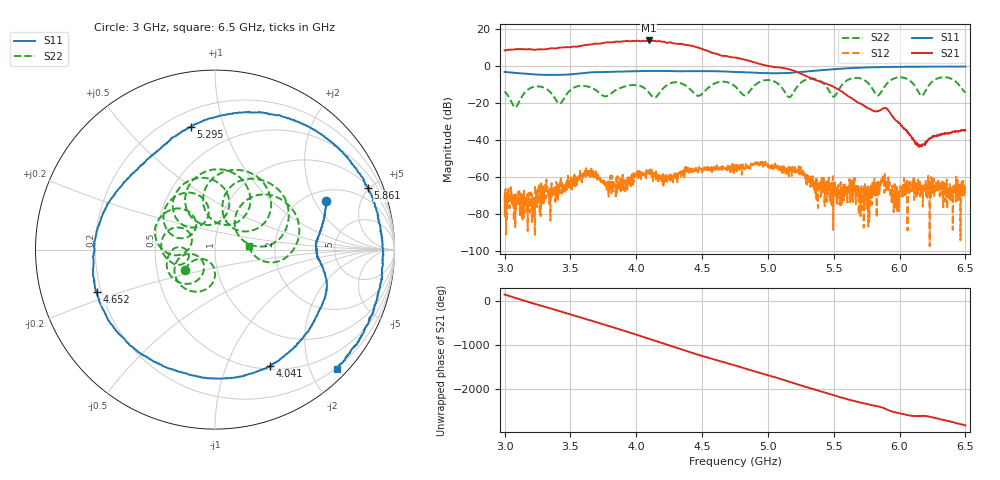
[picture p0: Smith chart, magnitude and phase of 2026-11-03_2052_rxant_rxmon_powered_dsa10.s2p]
! HEWLETT PACKARD,8720ES,MY41003347,7.72, via bringup/vna_tests.py
! rxant_rxmon_powered_dsa10
! measured 2026-11-03 20:53:22, 1601 points, 3000000000-6500000000 Hz, IF bandwidth 1000 Hz, source -40.00 dBm, kit CALK35MD
! board A, DSA 10.00 dB (set before each sweep)
# HZ S RI R 50
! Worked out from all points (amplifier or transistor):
!   1601 points, 3 GHz to 6.5 GHz, reference 50 ohm
!   highest |S21| = 13.7 dB at 4.096 GHz (marker M1)
!   |S21| within 3 dB of that: 3.577 GHz to 4.427 GHz (850.6 MHz wide, 21.3 % of centre)
!   unconditionally stable (mu >= 1): start of sweep to end of sweep
!   at 3.582 GHz: K = 97.68, MAG = 13.2 dB, |S12| = -61.5 dB
!   at 4.75 GHz: K = 90.95, MAG = 7.5 dB, |S12| = -55.7 dB
!   at 6.5 GHz: K = 4179.33, MAG = -24.7 dB, |S12| = -63.9 dB
!   S11 on the Smith chart (normalised r, x): 3 GHz: 2.47, +2.49; 4.041 GHz: 0.54, -1.44; 4.652 GHz: 0.18, -0.17; 5.295 GHz: 0.29, +0.78; 5.861 GHz: 1.09, +4.91; 6.5 GHz: 0.18, -2.44
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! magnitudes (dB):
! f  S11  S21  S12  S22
! 3 GHz  -3.4  8.3  -70.0  -13.9
! 3.081 GHz  -3.9  8.9  -87.5  -22.6
! 3.278 GHz  -4.9  8.8  -63.6  -11.4
! 3.418 GHz  -4.9  9.8  -69.1  -20.6
! 3.584 GHz  -4.1  10.8  -61.2  -10.8
! 4.041 GHz  -2.9  13.3  -59.3  -11.3
! 4.096 GHz  -2.9  13.7  -57.1  -14.5
! 4.168 GHz  -2.8  13.3  -62.0  -15.5
! 4.652 GHz  -3.1  5.4  -56.3  -8.6
! 4.75 GHz  -3.4  4.4  -55.7  -11.1
! 5.021 GHz  -4.1  -0.3  -54.4  -7.9
! 5.163 GHz  -3.9  -2.0  -56.4  -17.1
! 5.295 GHz  -3.1  -5.8  -59.0  -7.4
! 5.334 GHz  -2.9  -7.0  -60.4  -7.0
! 5.498 GHz  -1.9  -11.4  -65.3  -16.8
! 5.717 GHz  -1.0  -21.0  -77.8  -7.3
! 5.861 GHz  -0.7  -23.7  -63.1  -14.1
! 5.918 GHz  -0.7  -24.5  -67.3  -8.7
! 5.986 GHz  -0.6  -30.3  -74.8  -6.4
! 6.152 GHz  -0.5  -43.0  -64.5  -15.3
! 6.334 GHz  -0.5  -36.8  -66.4  -6.2
! 6.5 GHz  -0.5  -34.9  -63.9  -14.5
